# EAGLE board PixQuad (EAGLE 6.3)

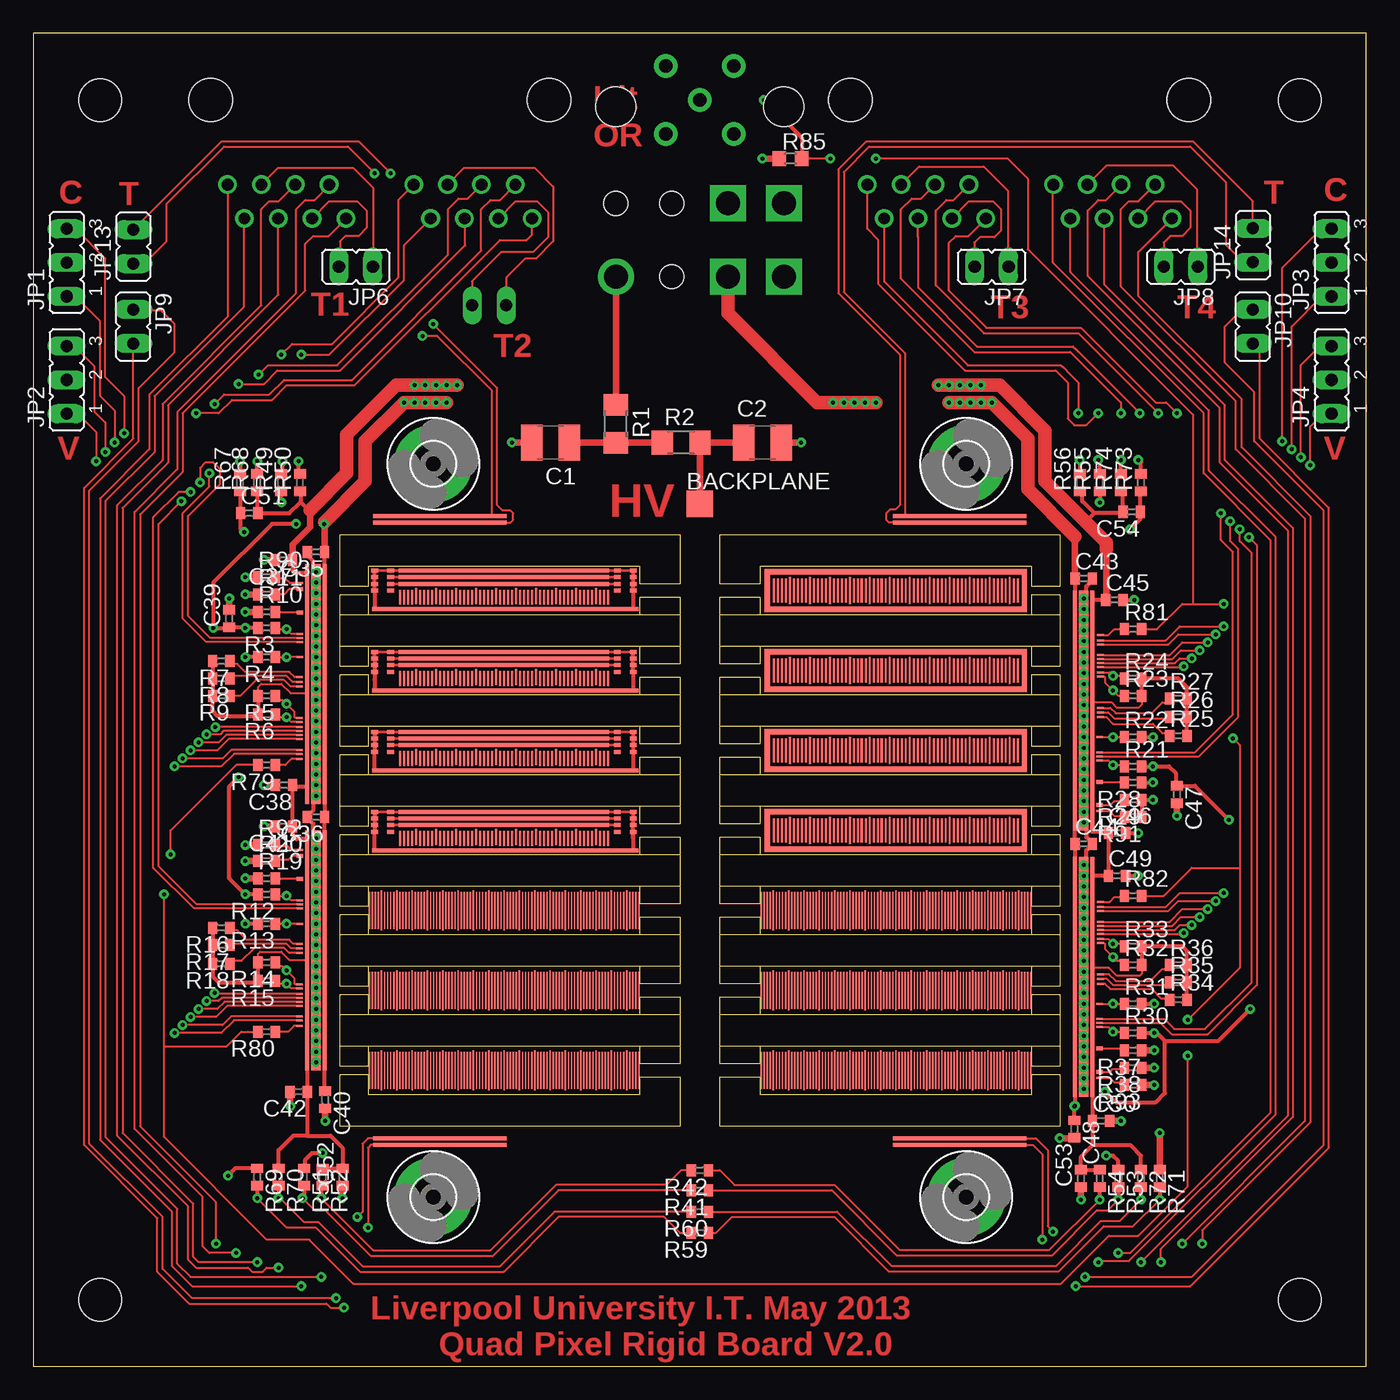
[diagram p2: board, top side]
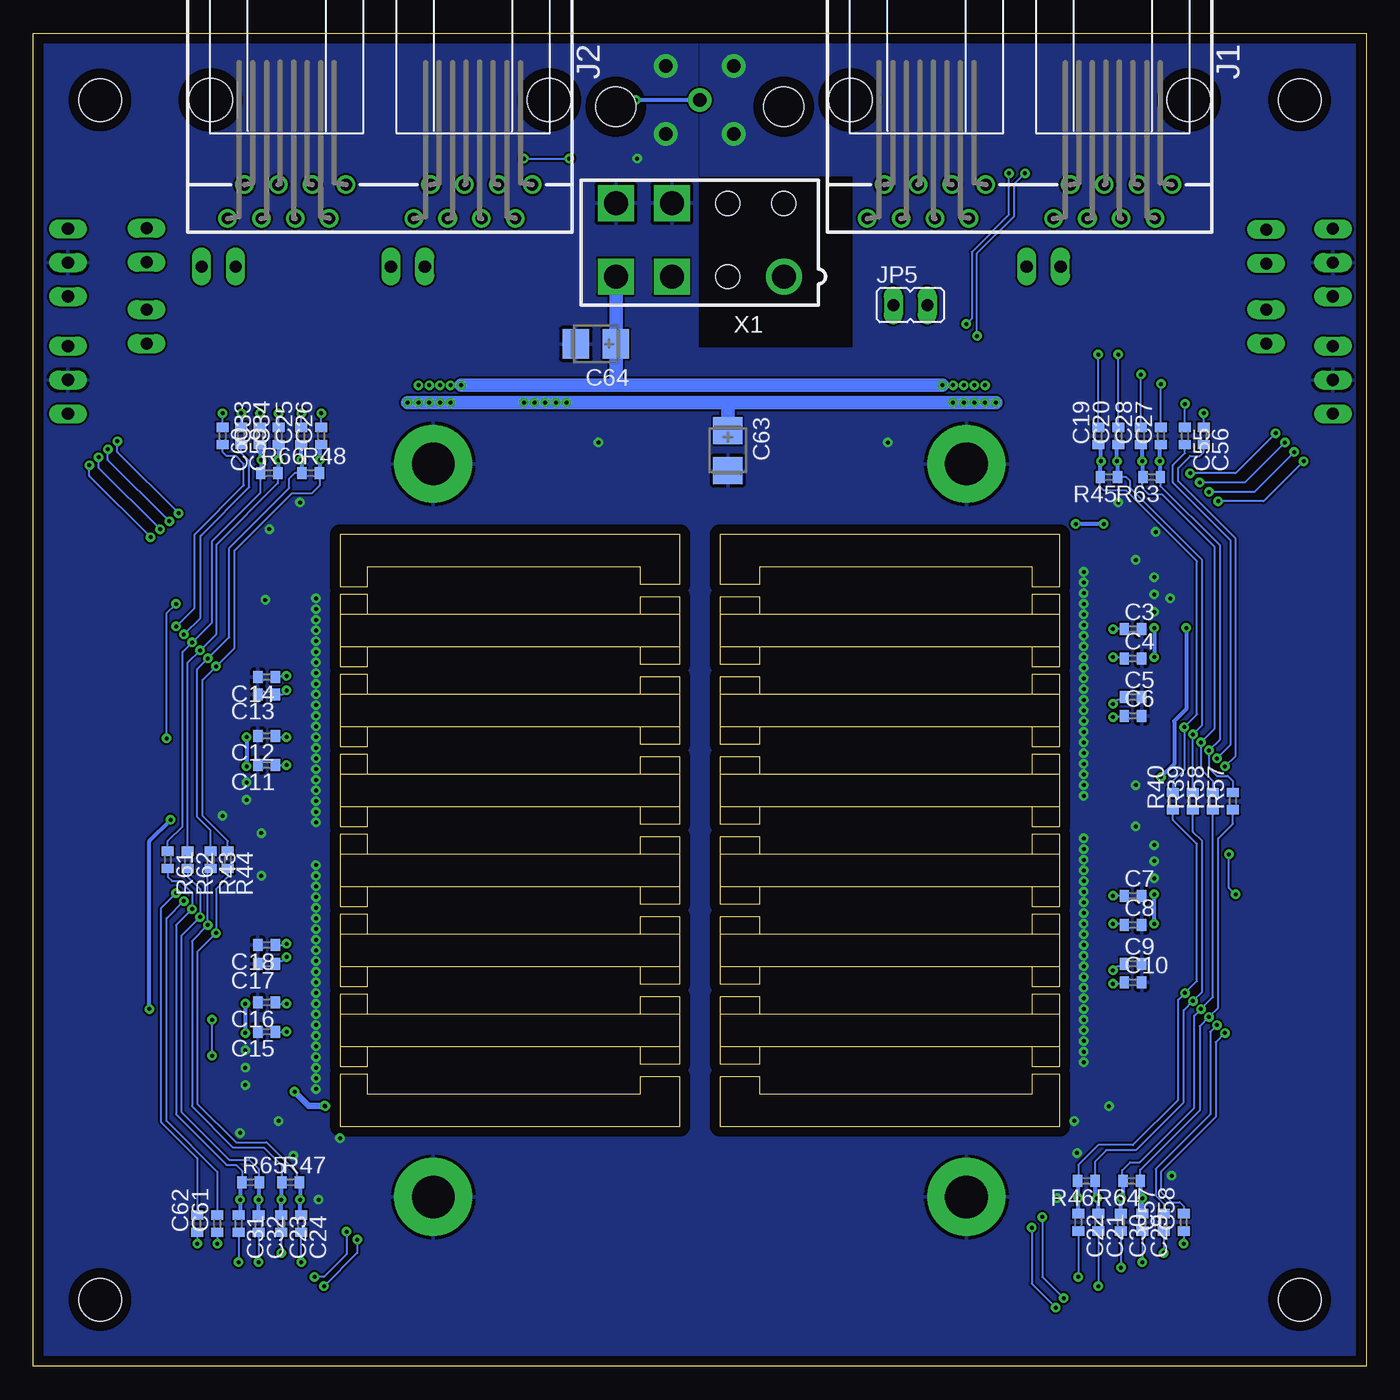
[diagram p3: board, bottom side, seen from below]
Size 100 x 100 mm. Coordinates in mm from the lower left corner, seen from the top.
Outline: 0,0 100,0 100,100 0,100 0,0
Copper layers (1+2*15+16): Top 0.035mm / dielectric 1.5mm / Route2 0.035mm / dielectric 0.15mm / Route15 0.035mm / dielectric 0.2mm / Bottom 0.035mm
Design rules "default *": minimum track width 10mil, minimum drill 24mil, track to track 6mil, track to pad 6mil, pad to pad 6mil, via to via 6mil, smd to smd 6mil, copper to edge 30mil, drill to drill 8mil, minimum pad ring 10mil, minimum via ring 8mil, stop-mask expansion 4mil, vias tented up to drill 0mil, thermal gap 10mil
Holes 3.2 mm at 5,5 5,95 95,95 95,5

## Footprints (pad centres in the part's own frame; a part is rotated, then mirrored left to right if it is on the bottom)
TP20SQ = smd 2 x 2: TP 0,0
C1210 = smd 1.6 x 2.7: 1 -1.4,0; 2 1.4,0
C0402 = smd 0.7 x 0.9: 1 -0.65,0; 2 0.65,0
CT3528 = smd 2 x 2.2: + -1.5,0; - 1.5,0
3,2-PAD = drill 3.2 pad 5.842: B3,2 0,0
557560-1 = drill 0.889: 1-1 -11.43,6.35; 1-2 -10.16,8.89; 1-3 -8.89,6.35; 1-4 -7.62,8.89; 1-5 -6.35,6.35; 1-6 -5.08,8.89; 1-7 -3.81,6.35; 1-8 -2.54,8.89; 2-1 2.54,6.35; 2-2 3.81,8.89; 2-3 5.08,6.35; 2-4 6.35,8.89; 2-5 7.62,6.35; 2-6 8.89,8.89; 2-7 10.16,6.35; 2-8 11.43,8.89 | hole 3.251: -12.7,0; 12.7,0
JP2 = drill 0.914 long: 1 -2.54,0; 2 0,0; 3 2.54,0
JP1 = drill 0.914 long: 1 0,-1.27; 2 0,1.27
JUMPER_JP1 = drill 0.914 long: 1 0,-1.27; 2 0,1.27
R1206 = smd 1.6 x 1.803: 1 -1.422,0; 2 1.422,0
R0402 = smd 0.7 x 0.9: 1 -0.65,0; 2 0.65,0
RCL_R0603 = smd 1 x 1.1: 1 -0.85,0; 2 0.85,0
FE-I4 = smd 0.15 x 0.5: AINJ(46) -4.45,-2; CAPM(47) -4.15,-2; CLK+(93) 2.55,-2.05; CLK-(92) 2.25,-2.05; CMD+(95) 3.15,-2.05; CMD-(94) 2.85,-2.05; DOB+(103) 3.95,-2.05; DOB-(104) 4.25,-2.05; GA0(67) -1.5,-2.05; GA1(68) -1.15,-2.05; GA2(69) -0.8,-2.05; P$1 4.65,-2.05; RESET1(45) -4.75,-2; RESET2(56) -3,-2; RESET3(88) 1.55,-2.05; RESET4(89) 1.85,-2.05; TDAC(11) -8.55,-2 | smd 18 x 0.7: GND -1,-0.8 | smd 0.3 x 0.5: IREF(33,34) -6.35,-2; VTHR(24,16) -8.1,-2 | smd 18 x 0.3: VDDA -1,-0.15; VDDD -1,-1.45
PA2 = smd 0.1 x 2.8: P$1 0,0; P$2 0.23,0; P$3 0.46,0; P$4 0.69,0; P$6 1.15,0; P$7 1.38,0; P$8 1.61,0; P$9 1.84,0; P$11 2.3,0; P$12 2.53,0; P$13 2.76,0; P$14 2.99,0; P$16 3.45,0; P$17 3.68,0; P$18 3.91,0; P$19 4.14,0; P$21 4.6,0; P$22 4.83,0; P$23 5.06,0; P$24 5.29,0; P$26 5.75,0; P$27 5.98,0; P$28 6.21,0; P$29 6.44,0; P$31 6.9,0; P$32 7.13,0; P$33 7.36,0; P$34 7.59,0; P$36 8.05,0; P$37 8.28,0; P$38 8.51,0; P$39 8.74,0; P$41 9.2,0; P$42 9.43,0; P$43 9.66,0; P$44 9.89,0; P$46 10.35,0; P$47 10.58,0; P$48 10.81,0; P$49 11.04,0; P$51 11.5,0; P$52 11.73,0; P$53 11.96,0; P$54 12.19,0; P$56 12.65,0; P$57 12.88,0; P$58 13.11,0; P$59 13.34,0; P$61 13.8,0; P$62 14.03,0; P$63 14.26,0; P$64 14.49,0; P$66 14.95,0; P$67 15.18,0; P$68 15.41,0; P$69 15.64,0; P$71 16.1,0; P$72 16.33,0; P$73 16.56,0; P$74 16.79,0; P$76 17.25,0; P$77 17.48,0; P$78 17.71,0; P$79 17.94,0; P$81 18.4,0; P$82 18.63,0; P$83 18.86,0; P$84 19.09,0; P$86 19.55,0; P$87 19.78,0; P$88 20.01,0; P$89 20.24,0 | smd 0.1 x 3: P$5 0.92,0; P$10 2.07,0; P$15 3.22,0; P$20 4.37,0; P$25 5.52,0; P$30 6.67,0; P$35 7.82,0; P$40 8.97,0; P$45 10.12,0; P$50 11.27,0; P$55 12.42,0; P$60 13.57,0; P$65 14.72,0; P$70 15.87,0; P$75 17.02,0; P$80 18.17,0; P$85 19.32,0
PA3 = smd 15.8 x 0.3: P$1 10.2,0.7; P$2 10.2,0.2; P$3 10.2,-0.3 | smd 0.5 x 0.3: P$4 0.5,0.7; P$5 0.5,0.2; P$6 0.5,-0.3; P$7 0.5,-0.8; P$8 1.7,0.7; P$9 1.7,0.2; P$10 1.7,-0.3; P$11 1.7,-0.8; P$12 18.7,0.7; P$13 18.7,0.2; P$14 18.7,-0.3; P$15 18.7,-0.8; P$16 19.9,0.7; P$17 19.9,0.2; P$18 19.9,-0.3; P$19 19.9,-0.8 | smd 20 x 0.3: P$20 10.3,-2.2 | smd 0.15 x 1.1: P$21 2.4,-1.3; P$22 2.7,-1.3; P$23 3,-1.3; P$24 3.3,-1.3; P$26 3.9,-1.3; P$27 4.2,-1.3; P$28 4.5,-1.3; P$29 4.8,-1.3; P$31 5.4,-1.3; P$32 5.7,-1.3; P$33 6,-1.3; P$34 6.3,-1.3; P$36 6.9,-1.3; P$37 7.2,-1.3; P$38 7.5,-1.3; P$39 7.8,-1.3; P$41 8.4,-1.3; P$42 8.7,-1.3; P$43 9,-1.3; P$44 9.3,-1.3; P$46 9.9,-1.3; P$47 10.2,-1.3; P$48 10.5,-1.3; P$49 10.8,-1.3; P$51 11.4,-1.3; P$52 11.7,-1.3; P$53 12,-1.3; P$54 12.3,-1.3; P$56 12.9,-1.3; P$57 13.2,-1.3; P$58 13.5,-1.3; P$59 13.8,-1.3; P$61 14.4,-1.3; P$62 14.7,-1.3; P$63 15,-1.3; P$64 15.3,-1.3; P$66 15.9,-1.3; P$67 16.2,-1.3; P$68 16.5,-1.3; P$69 16.8,-1.3; P$71 17.4,-1.3; P$72 17.7,-1.3; P$73 18,-1.3 | smd 0.15 x 1.2: P$25 3.6,-1.2; P$30 5.1,-1.2; P$35 6.6,-1.2; P$40 8.1,-1.2; P$45 9.6,-1.2; P$50 11.1,-1.2; P$55 12.6,-1.2; P$60 14.1,-1.2; P$65 15.6,-1.2; P$70 17.1,-1.2
PA1 = smd 19.7 x 0.4: P$1 9.9,1.4; P$2 9.9,-1.4 | smd 0.15 x 1.8: P$3 0.75,0; P$4 1.05,0; P$5 1.35,0; P$6 1.65,0; P$8 2.25,0; P$9 2.55,0; P$10 2.85,0; P$11 3.15,0; P$13 3.75,0; P$14 4.05,0; P$15 4.35,0; P$16 4.65,0; P$18 5.25,0; P$19 5.55,0; P$20 5.85,0; P$21 6.15,0; P$23 6.75,0; P$24 7.05,0; P$25 7.35,0; P$26 7.65,0; P$28 8.25,0; P$29 8.55,0; P$30 8.85,0; P$31 9.15,0; P$33 9.75,0; P$34 10.05,0; P$35 10.35,0; P$36 10.65,0; P$38 11.25,0; P$39 11.55,0; P$40 11.85,0; P$41 12.15,0; P$43 12.75,0; P$44 13.05,0; P$45 13.35,0; P$46 13.65,0; P$48 14.25,0; P$49 14.55,0; P$50 14.85,0; P$51 15.15,0; P$53 15.75,0; P$54 16.05,0; P$55 16.35,0; P$56 16.65,0; P$58 17.25,0; P$59 17.55,0; P$60 17.85,0; P$61 18.15,0; P$63 18.75,0; P$64 19.05,0 | smd 0.15 x 2: P$7 1.95,0; P$12 3.45,0; P$17 4.95,0; P$22 6.45,0; P$27 7.95,0; P$32 9.45,0; P$37 10.95,0; P$42 12.45,0; P$47 13.95,0; P$52 15.45,0; P$57 16.95,0; P$62 18.45,0 | smd 0.4 x 2.4: P$65 19.55,0; P$66 0.25,0
DORT = smd 10 x 0.3: P$1 5,0; P$2 5,0.5
FE-I4_5566-8 = drill 1.8: 1 6.3,-2.75 | drill 1.8 square: 3 -2.1,-2.75; 4 -6.3,-2.75; 7 -2.1,2.75; 8 -6.3,2.75 | hole 1.8: 2.1,-2.75; 2.1,2.75; 6.3,2.75 | hole 3: -6.3,10; 6.3,10

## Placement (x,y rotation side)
BACKPLANE  TPSQTP20SQ  [TP20SQ]  50,64.7 0 top
C1  10n  [C1210]  38.8,69.3 180 top
C2  10n  [C1210]  54.7,69.3 0 top
C3  100n  [C0402]  17.5,55.3 0 bottom
C4  100n  [C0402]  17.5,53.1 0 bottom
C5  100n  [C0402]  17.5,50.2 0 bottom
C6  100n  [C0402]  17.5,48.8 0 bottom
C7  100n  [C0402]  17.5,35.3 0 bottom
C8  100n  [C0402]  17.5,33.1 0 bottom
C9  100n  [C0402]  17.5,30.2 0 bottom
C10  100n  [C0402]  17.5,28.8 0 bottom
C11  100n  [C0402]  82.5,45.1 180 bottom
C12  100n  [C0402]  82.5,47.3 180 bottom
C13  100n  [C0402]  82.5,50.4 180 bottom
C14  100n  [C0402]  82.5,51.7 180 bottom
C15  100n  [C0402]  82.5,25.1 180 bottom
C16  100n  [C0402]  82.5,27.3 180 bottom
C17  100n  [C0402]  82.5,30.2 180 bottom
C18  100n  [C0402]  82.5,31.6 180 bottom
C19  100n  [C0402]  20.1,69.8 90 bottom
C20  100n  [C0402]  18.6,69.8 90 bottom
C21  100n  [C0402]  20.1,10.8 270 bottom
C22  100n  [C0402]  21.6,10.8 270 bottom
C23  100n  [C0402]  81.4,10.7 270 bottom
C24  100n  [C0402]  79.9,10.7 270 bottom
C25  100n  [C0402]  79.9,69.8 90 bottom
C26  100n  [C0402]  78.4,69.8 90 bottom
C27  100n  [C0402]  15.4,69.8 90 bottom
C28  100n  [C0402]  16.9,69.8 90 bottom
C29  100n  [C0402]  16.8,10.8 270 bottom
C30  100n  [C0402]  18.4,10.8 270 bottom
C31  100n  [C0402]  84.6,10.7 270 bottom
C32  100n  [C0402]  83.1,10.7 270 bottom
C33  100n  [C0402]  83,69.8 90 bottom
C34  100n  [C0402]  81.6,69.8 90 bottom
C35  100n  [C0402]  21.2,61.1 180 top
C36  100n  [C0402]  21.2,41.2 180 top
C37  100n  [C0402]  18.8,60.5 180 top
C38  100n  [C0402]  18.8,43.6 180 top
C39  100n  [C0402]  14.7,56.1 90 top
C40  100n  [C0402]  21.9,20 270 top
C41  100n  [C0402]  18.8,40.5 180 top
C42  100n  [C0402]  19.9,20.6 180 top
C43  100n  [C0402]  78.8,59.1 0 top
C44  100n  [C0402]  78.8,39.2 0 top
C45  100n  [C0402]  81.1,57.5 0 top
C46  100n  [C0402]  81.3,40 0 top
C47  100n  [C0402]  85.8,42.9 270 top
C48  100n  [C0402]  78.1,17.8 270 top
C49  100n  [C0402]  81.3,36.8 0 top
C50  100n  [C0402]  80.1,18.4 0 top
C51  100n  [C0402]  16.2,64 0 top
C52  100n  [C0402]  23.2,14.2 90 top
C53  100n  [C0402]  78.6,14.1 90 top
C54  100n  [C0402]  82.4,64.1 180 top
C55  100n  [C0402]  13.6,69.8 270 bottom
C56  100n  [C0402]  12.2,69.8 270 bottom
C57  100n  [C0402]  15.2,10.8 90 bottom
C58  100n  [C0402]  13.7,10.8 90 bottom
C59  100n  [C0402]  84.4,69.8 270 bottom
C60  100n  [C0402]  85.8,69.8 270 bottom
C61  100n  [C0402]  86.2,10.7 90 bottom
C62  100n  [C0402]  87.7,10.7 90 bottom
C63  10u  [CT3528]  47.9,68.7 270 bottom
C64  10u  [CT3528]  57.8,76.7 180 bottom
H1  [3,2-PAD]  30,67.7 0 top
H2  [3,2-PAD]  30,12.7 0 top
H3  [3,2-PAD]  70,67.7 0 top
H4  substrate contacts  [3,2-PAD]  70,12.7 0 top
J1  [557560-1]  26,95 180 bottom
J2  [557560-1]  74,95 180 bottom
JP1  [JP2]  2.5,82.8 90 top
JP2  [JP2]  2.5,74 90 top
JP3  [JP2]  97.4,82.8 90 top
JP4  [JP2]  97.4,74 90 top
JP5  [JP1]  34.2,79.6 270 bottom
JP6  [JP1]  24.2,82.5 90 top
JP7  [JP1]  71.9,82.5 90 top
JP8  [JP1]  86.1,82.5 90 top
JP9  [JUMPER_JP1]  7.5,78 180 top
JP10  [JUMPER_JP1]  91.5,78 180 top
JP13  [JUMPER_JP1]  7.5,84 0 top
JP14  [JUMPER_JP1]  91.5,84.1 0 top
R1  1k  [R1206]  43.7,70.7 270 top
R2  1k  [R1206]  48.6,69.3 0 top
R3  10k  [R0402]  17.5,55.4 180 top
R4  10k  [R0402]  17.5,53.2 180 top
R5  10k  [R0402]  17.5,50.3 180 top
R6  10k  [R0402]  17.5,48.9 180 top
R7  zero  [R0402]  14.1,52.9 180 top
R8  zero  [R0402]  14.1,51.6 180 top
R9  zero  [R0402]  14.1,50.3 180 top
R10  opt  [R0402]  17.5,56.6 0 top
R11  10k  [R0402]  17.5,57.9 0 top
R12  10k  [R0402]  17.5,35.4 180 top
R13  10k  [R0402]  17.5,33.2 180 top
R14  10k  [R0402]  17.5,30.3 180 top
R15  10k  [R0402]  17.5,28.9 180 top
R16  zero  [R0402]  14.1,32.9 180 top
R17  zero  [R0402]  14.1,31.6 180 top
R18  zero  [R0402]  14.1,30.2 180 top
R19  opt  [R0402]  17.5,36.6 0 top
R20  10k  [R0402]  17.5,37.9 0 top
R21  10k  [R0402]  82.5,45 0 top
R22  10k  [R0402]  82.5,47.2 0 top
R23  10k  [R0402]  82.5,50.3 0 top
R24  10k  [R0402]  82.5,51.6 0 top
R25  zero  [R0402]  85.9,47.3 0 top
R26  zero  [R0402]  85.9,48.7 0 top
R27  zero  [R0402]  85.9,50.1 0 top
R28  opt  [R0402]  82.5,43.8 180 top
R29  10k  [R0402]  82.5,42.5 180 top
R30  10k  [R0402]  82.5,25 0 top
R31  10k  [R0402]  82.5,27.2 0 top
R32  10k  [R0402]  82.5,30.1 0 top
R33  10k  [R0402]  82.5,31.5 0 top
R34  zero  [R0402]  85.9,27.5 0 top
R35  zero  [R0402]  85.9,28.8 0 top
R36  zero  [R0402]  85.9,30.1 0 top
R37  opt  [R0402]  82.5,23.7 180 top
R38  10k  [R0402]  82.5,22.4 180 top
R39  opt  [R0402]  13,42.4 90 bottom
R40  opt  [R0402]  14.5,42.4 90 bottom
R41  opt  [R0402]  50,13.2 180 top
R42  opt  [R0402]  50,14.7 180 top
R43  opt  [R0402]  86.7,38 270 bottom
R44  opt  [R0402]  85.4,38 270 bottom
R45  110  [R0402]  19.3,66.7 180 bottom
R46  110  [R0402]  21,13.9 180 bottom
R47  110  [R0402]  80.7,13.8 0 bottom
R48  110  [R0402]  79.2,67 0 bottom
R49  1k  [R0402]  18.6,66.3 90 top
R50  1k  [R0402]  20,66.3 90 top
R51  1k  [R0402]  20.3,14.2 270 top
R52  1k  [R0402]  21.7,14.2 270 top
R53  1k  [R0402]  81.4,14.1 270 top
R54  1k  [R0402]  80,14.1 270 top
R55  1k  [R0402]  80,66.3 90 top
R56  1k  [R0402]  78.5,66.3 90 top
R57  opt  [R0402]  10,42.4 90 bottom
R58  opt  [R0402]  11.5,42.4 90 bottom
R59  opt  [R0402]  50,10 180 top
R60  opt  [R0402]  50,11.6 180 top
R61  opt  [R0402]  89.9,38 270 bottom
R62  opt  [R0402]  88.4,38 270 bottom
R63  110  [R0402]  16.1,66.7 180 bottom
R64  110  [R0402]  17.6,13.9 180 bottom
R65  110  [R0402]  83.7,13.8 0 bottom
R66  110  [R0402]  82.3,67 0 bottom
R67  1k  [R0402]  15.5,66.3 90 top
R68  1k  [R0402]  16.8,66.3 90 top
R69  1k  [R0402]  16.8,14.2 270 top
R70  1k  [R0402]  18.4,14.2 270 top
R71  1k  [R0402]  84.5,14.1 270 top
R72  1k  [R0402]  83.1,14.1 270 top
R73  1k  [R0402]  83.1,66.3 90 top
R74  1k  [R0402]  81.6,66.3 90 top
R79  1k  [R0402]  17.5,45.1 180 top
R80  1k  [R0402]  17.5,25.1 180 top
R81  1k  [R0402]  82.5,55.3 0 top
R82  1k  [R0402]  82.5,35.3 0 top
R85  51  [RCL_R0603]  56.8,90.6 0 top
R90  200k  [R0402]  17.5,59.2 0 top
R91  200k  [R0402]  82.5,41.2 180 top
R92  200k  [R0402]  17.5,39.1 0 top
R93  200k  [R0402]  82.5,21.1 180 top
U$1  FE_I4ASIC  [FE-I4]  22,50.2 270 top
U$2  FE_I4ASIC  [FE-I4]  22,30.2 270 top
U$3  FE_I4ASIC  [FE-I4]  78,50.2 90 top
U$4  FE_I4ASIC  [FE-I4]  78,30.2 90 top
U$5  PA2  [PA2]  25.2,34.2 0 top
U$6  PA2  [PA2]  25.2,28.2 0 top
U$7  PA2  [PA2]  54.6,34.2 0 top
U$8  PA2  [PA2]  25.2,22.2 0 top
U$9  PA2  [PA2]  54.6,28.2 0 top
U$10  PA2  [PA2]  54.6,22.2 0 top
U$11  PA3  [PA3]  25.1,59 0 top
U$12  PA1  [PA1]  54.8,58.2 0 top
U$13  PA1  [PA1]  54.8,52.2 0 top
U$14  PA1  [PA1]  54.8,46.2 0 top
U$15  PA1  [PA1]  54.8,40.2 0 top
U$16  PA3  [PA3]  25.1,52.9 0 top
U$17  DORT  [DORT]  25.5,63.3 0 top
U$18  DORT  [DORT]  64.5,63.3 0 top
U$19  PA3  [PA3]  25.1,46.9 0 top
U$20  PA3  [PA3]  25.1,40.9 0 top
U$21  DORT  [DORT]  25.5,16.6 0 top
U$22  DORT  [DORT]  64.5,16.6 0 top
X1  FE-I4_5566-8  [FE-I4_5566-8]  50,84.5 0 bottom

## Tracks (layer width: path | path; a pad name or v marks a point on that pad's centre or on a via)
AINJ1  (via drill 0.3)
  Top 0.15: U$1.AINJ(46) 13.25,54.65 11.6,56.3 11.6,63.8 14,66.2 14,67.3 13.5,67.8 12.9,67.8 12.5,67.4 v12.5,66.3 | JP1.1 2.56,80.2 3.2,80.2 5,78.4 5,72.8 6.1,71.7 v6.1,69.3
  Bottom 0.15: v6.1,69.3 9.1,66.3 v12.5,66.3
AINJ2  (via drill 0.3)
  Top 0.15: U$2.AINJ(46) 12.25,34.65 9.4,37.5 9.4,63.2 v11.1,64.9 | JP2.1 3.34,71.46 4.7,70.1 v4.7,67.9
  Bottom 0.15: v4.7,67.9 7.7,64.9 v11.1,64.9
AINJ3  (via drill 0.3)
  Top 0.15: U$3.AINJ(46) 87.45,45.75 90.4,48.7 90.4,61.3 89.8,61.9 v89.8,63.4 | v94.4,68.8 94.4,78 96.6,80.2 97.34,80.2 JP3.1
  Bottom 0.15: v89.8,63.4 94.4,68 v94.4,68.8
AINJ4  (via drill 0.3)
  Top 0.15: U$4.AINJ(46) 84.55,25.75 85.4,24.9 88.1,24.9 91.8,28.6 91.8,61.6 v91.2,62.2 | JP4.1 97.24,71.3 96.6,71.3 95.8,70.5 v95.8,67.6
  Bottom 0.15: v91.2,62.2 95.8,66.8 v95.8,67.6
C1.1  (via drill 0.3)
  Top 0.15: v18.6,75.9 19.4,76.7 22.4,76.7 27.4,81.7 27.4,87.51 J1.2-1 28.5,88.61
  Bottom 0.15: C20.2 v18.6,75.9
C1.2  (via drill 0.3)
  Top 0.15: v20.1,75.9 22.2,75.9 27.8,81.5 27.8,84.1 J1.2-2
  Bottom 0.15: C19.2 v20.1,75.9
C1.4  (via drill 0.3)
  Top 0.15: v15.4,73.7 17.3,73.7 18.3,74.7 23,74.7 32.4,84.1 32.4,86.06 J1.2-4
  Bottom 0.15: C27.2 v15.4,73.7
C1.5  (via drill 0.3)
  Top 0.15: v16.9,74.4 17.6,75.1 22.8,75.1 31.1,83.4 31.1,86.8 31.9,87.6 32.57,87.6 J1.2-5
  Bottom 0.15: C28.2 v16.9,74.4
C1.7  (via drill 0.3)
  Top 0.15: v13.6,72.2 14.3,72.9 17.7,72.9 18.8,74 23.9,74 33.6,83.7 33.6,86.8 34.3,87.5 35.01,87.5 J1.2-7
  Bottom 0.15: C55.1 v13.6,72.2
C1.8  (via drill 0.3)
  Top 0.15: v12.2,71.5 13.9,71.5 14.9,72.5 17.9,72.5 19,73.6 24.1,73.6 35,84.5 37,84.5 37.4,84.9 37.4,86.08 J1.2-8
  Bottom 0.15: C56.1 v12.2,71.5
C2.1  (via drill 0.3)
  Top 0.15: J1.1-1 14.6,88.62 14.6,78.8 8.7,72.9 8.7,68.8 5,65.1 5,17 10.4,11.6 10.4,7.5 11.9,6 v20.1,6
  Bottom 0.15: C21.2 v20.1,6
C2.2  (via drill 0.3)
  Top 0.15: J1.1-2 15.8,86.07 15.8,79.5 9.1,72.8 9.1,68.6 5.4,64.9 5.4,17.2 10.8,11.8 10.8,7.7 11.8,6.7 v21.6,6.7
  Bottom 0.15: C22.2 v21.6,6.7
C2.4  (via drill 0.3)
  Top 0.15: v16.8,7.8 12.4,7.8 12,8.2 12,12.2 6.7,17.5 6.7,64.4 10.1,67.8 10.1,72.1 18.38,80.38 J1.1-4
  Bottom 0.15: C29.2 v16.8,7.8
C2.5  (via drill 0.3)
  Top 0.15: v18.4,7.4 17.5,7.4 17.2,7.1 16.4,7.1 16.1,7.4 12.2,7.4 11.6,8 11.6,12 6.3,17.3 6.3,64.6 9.7,68 9.7,72.2 17.1,79.6 17.1,86.8 17.7,87.4 18.4,87.4 J1.1-5
  Bottom 0.15: C30.2 v18.4,7.4
C2.7  (via drill 0.3)
  Top 0.15: v15.2,8.5 13.2,8.5 12.7,9 12.7,12.7 7.6,17.8 7.6,64.1 10.8,67.3 10.8,71.6 19.7,80.5 19.7,86.8 20.4,87.5 21.1,87.5 22.19,88.59 J1.1-7
  Bottom 0.15: C57.1 v15.2,8.5
C2.8  (via drill 0.3)
  Top 0.15: J1.1-8 22.15,84.8 21,84.8 20.4,84.2 20.4,80.7 11.2,71.5 11.2,67.1 8,63.9 8,18 13.7,12.3 v13.7,9.2
  Bottom 0.15: C58.1 v13.7,9.2
C3.1  (via drill 0.3)
  Top 0.15: v79.9,71.5 79,70.6 78.1,70.6 77.6,71.1 77.6,73.8 76.7,74.7 69.9,74.7 63.4,81.2 63.4,84.5 62.57,85.33 J2.1-1
  Bottom 0.15: C25.2 v79.9,71.5
C3.2  (via drill 0.3)
  Top 0.15: J2.1-2 63.84,81.36 70.1,75.1 77.1,75.1 77.3,74.9 77.75,74.45 78.4,73.8 v78.4,71.5
  Bottom 0.15: C26.2 v78.4,71.5
C3.4  (via drill 0.3)
  Top 0.15: J2.1-4 66.38,84.72 66.4,84.7 66.4,80.9 70.8,76.5 78,76.5 78.2,76.3 78.35,76.15 v83,71.5
  Bottom 0.15: C33.2 v83,71.5
C3.5  (via drill 0.3)
  Top 0.15: v81.6,71.5 81.6,72.3 77.8,76.1 70.6,76.1 65.1,81.6 65.1,86.8 65.9,87.6 66.6,87.6 J2.1-5
  Bottom 0.15: C34.2 v81.6,71.5
C3.7  (via drill 0.3)
  Top 0.15: v84.4,71.5 78.4,77.5 71.3,77.5 67.7,81.1 67.7,86.7 68.5,87.5 69.04,87.5 J2.1-7
  Bottom 0.15: C59.1 v84.4,71.5
C3.8  (via drill 0.3)
  Top 0.15: v85.8,71.5 85,72.3 84.2,72.3 78.6,77.9 71.5,77.9 68.7,80.7 68.7,84.3 69.2,84.8 70.15,84.8 J2.1-8 71.5,86.07
  Bottom 0.15: C60.1 v85.8,71.5
C4.1  (via drill 0.3)
  Top 0.15: v81.4,8.5 82.3,8.5 92.8,19 92.8,62 87.8,67 87.8,71.5 76.5,82.8 76.5,88.61 J2.2-1
  Bottom 0.15: C23.2 v81.4,8.5
C4.2  (via drill 0.3)
  Top 0.15: v79.9,7.8 80,7.9 82.2,7.9 93.2,18.9 93.2,62.2 88.2,67.2 88.2,71.7 77.81,82.09 J2.2-2
  Bottom 0.15: v79.9,7.8 C24.2
C4.4  (via drill 0.3)
  Top 0.15: v84.6,7.8 84.6,8.8 94.5,18.7 94.5,62.9 89.4,68 89.4,72.1 80.35,81.15 J2.2-4
  Bottom 0.15: C31.2 v84.6,7.8
C4.5  (via drill 0.3)
  Top 0.15: v83.1,7.8 94.1,18.8 94.1,62.7 89,67.8 89,71.9 79.1,81.8 79.1,86.7 79.9,87.5 80.47,87.5 J2.2-5
  Bottom 0.15: C32.2 v83.1,7.8
C4.7  (via drill 0.3)
  Top 0.15: v86.2,9.2 95.4,18.4 95.4,63.6 90.2,68.8 90.2,72.4 81.6,81 81.6,86.8 82.2,87.4 82.91,87.4 J2.2-7
  Bottom 0.15: C61.1 v86.2,9.2
C4.8  (via drill 0.3)
  Top 0.15: J2.2-8 85.41,86.11 82.9,83.6 82.9,80.3 90.65,72.55 90.65,68.95 95.8,63.8 95.8,18.3 87.7,10.2 v87.7,9.2
  Bottom 0.15: C62.1 v87.7,9.2
CAPM1  (via drill 0.3)
  Top 0.15: U$1.CAPM(47) 12.95,54.35 11.2,56.1 11.2,64 13.2,66 v13.2,67 | JP1.3 2.54,85.3 3.2,85.3 5.4,83.1 5.4,74.2 6.8,72.8 v6.8,70
  Bottom 0.15: v6.8,70 9.8,67 v13.2,67
CAPM2  (via drill 0.3)
  Top 0.15: U$2.CAPM(47) 12.05,34.35 9,37.4 9,63.7 10.9,65.6 v11.8,65.6 | 2.54,76.5 JP2.3 3.06,76.54 4.6,75 4.6,71.6 5.4,70.8 v5.4,68.6
  Bottom 0.15: v5.4,68.6 8.4,65.6 v11.8,65.6
CAPM3  (via drill 0.3)
  Top 0.15: U$3.CAPM(47) 87.15,46.05 90,48.9 90,61.1 89.1,62 v89.1,64 | v93.7,69.4 93.7,82.4 96.7,85.4 97.34,85.4 JP3.3
  Bottom 0.15: v89.1,64 93.7,68.6 v93.7,69.4
CAPM4  (via drill 0.3)
  Top 0.15: U$4.CAPM(47) 84.85,26.05 85.6,25.3 87.9,25.3 91.4,28.8 91.4,61 90.5,61.9 v90.5,62.8 | v95.1,68.2 95.1,75.1 96.6,76.6 97.34,76.6 JP4.3
  Bottom 0.15: v90.5,62.8 95.1,67.4 v95.1,68.2
CLK1+  (via drill 0.3)
  Top 0.15: U$1.CLK+(93) 14.25,47.65 14,47.4 v13,47.4
  Top 0.3: R49.2 18.7,66.95 v18.7,67.9
  Bottom 0.15: R39.2 v13,47.4 12.3,48.1 12.3,60.5 17.7,65.9 17.7,66.4 18,66.7 R45.1 18.65,66.9 R49.2
  Bottom 0.3: C20.1 18.7,69.05 v18.7,67.9 18.65,67.85 R45.1
CLK1-  (via drill 0.3)
  Top 0.15: U$1.CLK-(92) v13.65,47.95
  Top 0.3: R50.2 19.9,66.95 v19.9,67.9
  Bottom 0.15: R40.2 14.5,43.9 13.65,44.75 v13.65,47.95 12.7,48.9 12.7,60.4 18,65.7 19.7,65.7 20,66 20,66.65 R45.2
  Bottom 0.3: C19.1 19.9,68.95 v19.9,67.9 19.95,67.85 R45.2
CLK2+  (via drill 0.3)
  Top 0.15: U$2.CLK+(93) 14.15,27.65 13.9,27.4 v13,27.4 | R41.2 39.4,13.2 34.5,8.3 25.3,8.3 21.9,11.7 21.1,11.7 v20.2,12.6
  Top 0.3: 20.2,13.45 R51.2 20.3,12.7 v20.2,12.6
  Bottom 0.15: R39.1 13,40.1 12.3,39.4 12.3,28.1 v13,27.4 13.7,26.7 13.7,19.8 17.3,16.2 19.5,16.2 20.35,15.35 R46.1
  Bottom 0.3: R46.1 20.35,12.75 v20.2,12.6 20.1,12.5 C21.1
CLK2-  (via drill 0.3)
  Top 0.15: U$2.CLK-(92) 13.65,27.95 v13.6,28 | R42.2 48.6,14.7 47.5,13.6 39.2,13.6 34.3,8.7 25.5,8.7 v21.6,12.6
  Top 0.3: R52.2 21.6,13.45 v21.6,12.6
  Bottom 0.15: v13.6,28 12.7,28.9 12.7,39.2 14.5,41 R40.1 | v13.6,28 13.7,27.9 | v13.6,28 14.1,27.5 14.1,20 17.5,16.6 20.1,16.6 21.6,15.1 21.6,13.95 R46.2 | 21.65,12.65 v21.6,12.6
  Bottom 0.3: R46.2 21.65,12.65 | C22.1 v21.6,12.6
CLK3+  (via drill 0.3)
  Top 0.15: U$3.CLK+(93) 85.65,52.75 86,53.1 v86.9,53.1
  Top 0.3: R55.2 80,67.9 v79.9,68
  Bottom 0.15: R43.1 86.7,40.2 87.7,41.2 87.7,52.3 v86.9,53.1 85.3,54.7 85.3,61.4 80.8,65.9 80.8,66.6 80.4,67 R48.1
  Bottom 0.3: C25.1 v79.9,68 79.85,67.95 R48.1
CLK3-  (via drill 0.3)
  Top 0.15: U$3.CLK-(92) 86.25,52.45 v86.3,52.5
  Top 0.3: v78.5,68 R56.2
  Bottom 0.15: R44.1 85.4,39.4 87.3,41.3 87.3,51.5 v86.3,52.5 84.9,53.9 84.9,61.2 80.6,65.5 79.1,65.5 78.5,66.1 R56.2 R48.2
  Bottom 0.3: C26.1 78.5,69.05 v78.5,68 78.5,67.05 R48.2
CLK4+  (via drill 0.3)
  Top 0.15: U$4.CLK+(93) 85.65,32.75 86,33.1 v86.9,33.1 | R41.1 59.9,13.2 64.8,8.3 76.4,8.3 79.8,11.7 80.6,11.7 v81.4,12.5
  Top 0.3: R53.2 v81.4,12.5
  Bottom 0.15: R43.2 86.9,37.15 v86.9,33.1 88.1,31.9 88.1,19.5 85,16.4 82.7,16.4 81.35,15.05 R47.1
  Bottom 0.3: C23.1 v81.4,12.5 81.4,13.75 R47.1
CLK4-  (via drill 0.3)
  Top 0.15: U$4.CLK-(92) 86.25,32.45 v86.3,32.5 | R42.1 51.5,14.7 52.6,13.6 60.1,13.6 65,8.7 76.2,8.7 v80,12.5
  Top 0.3: v80,12.5 R54.2
  Bottom 0.15: R44.2 85.4,36.7 86.3,35.8 v86.3,32.5 87.7,31.1 87.7,19.7 84.8,16.8 82.5,16.8 80.2,14.5 80.2,13.95 R47.2
  Bottom 0.3: C24.1 80,11.45 v80,12.5 80,13.75 R47.2
CMD1+  (via drill 0.3)
  Top 0.15: U$1.CMD+(95) 14.65,47.05 13.8,46.2 v11.8,46.2
  Top 0.3: v15.5,67.9 R67.2
  Bottom 0.15: R57.2 10,43.9 10.4,44.3 11.2,44.3 11.8,44.9 v11.8,46.2 11,47 11,61.6 15.45,66.05 R63.1
  Bottom 0.3: C27.1 15.5,69.05 v15.5,67.9 15.45,67.85 R63.1
CMD1-  (via drill 0.3)
  Top 0.15: U$1.CMD-(94) 14.45,47.35 13.9,46.8 v12.4,46.8
  Top 0.3: R68.2 v16.8,67.9
  Bottom 0.15: R58.2 11.5,43.9 12.4,44.8 v12.4,46.8 11.4,47.8 11.4,61.5 15.3,65.4 16.3,65.4 16.8,65.9 16.8,66.65 R63.2
  Bottom 0.3: C28.1 16.8,69.05 v16.8,67.9 16.75,67.85 R63.2
CMD2+  (via drill 0.3, 0.3 pad 0.7)
  Top 0.15: U$2.CMD+(95) 14.55,27.05 13.7,26.2 v11.8,26.2 | R59.2 48.5,10 47.3,11.2 39.4,11.2 35.3,7.1 24.5,7.1 21.2,10.4 19,10.4 v16.8,12.6
  Top 0.3: 17.1,13.45 R69.2 v16.8,12.6
  Bottom 0.15: R57.1 10,40.7 11.1,39.6 11.1,26.9 v11.8,26.2 12.5,25.5 12.5,19.2 16.95,14.75 R64.1
  Bottom 0.3: C29.1 v16.8,12.6 16.95,12.75 R64.1
CMD2-  (via drill 0.3)
  Top 0.15: U$2.CMD-(94) 14.35,27.35 13.8,26.8 v12.4,26.8 | R60.2 39.1,11.6 35,7.5 24.7,7.5 21.4,10.8 20.3,10.8 18.5,12.6 v18.4,12.6
  Top 0.3: 18.6,13.35 R70.2 v18.4,12.6
  Bottom 0.15: v12.4,26.8 11.5,27.7 R58.1 | v12.4,26.8 12.5,26.7 | v12.4,26.8 12.9,26.3 12.9,19.4 17,15.3 17.7,15.3 18.3,14.7 18.3,13.95 R64.2
  Bottom 0.3: R64.2 18.25,12.75 v18.4,12.6 C30.1
CMD3+  (via drill 0.3)
  Top 0.15: U$3.CMD+(95) 85.25,53.35 86.2,54.3 v88.1,54.3
  Top 0.3: R73.2 83.1,67.8 v82.9,68
  Bottom 0.15: R61.1 89.9,39.4 88.8,40.5 88.8,53.6 v88.1,54.3 86.6,55.8 86.6,61.9 83,65.5 83,66.95 R66.1 82.9,66.95
  Bottom 0.3: C33.1 83,68.1 v82.9,68 82.9,67.05 R66.1
CMD3-  (via drill 0.3)
  Top 0.15: U$3.CMD-(94) 85.45,53.05 86.1,53.7 v87.5,53.7
  Top 0.3: R74.2 v81.6,68
  Bottom 0.15: R62.1 88.4,52.8 v87.5,53.7 86.25,54.95 86.25,61.65 81.65,66.25 R66.2
  Bottom 0.3: C34.1 v81.6,68 81.6,67.05 R66.2
CMD4+  (via drill 0.3)
  Top 0.15: U$4.CMD+(95) 85.25,33.35 86.2,34.3 v88.1,34.3 | R59.1 51.2,10 52.4,11.2 60.1,11.2 64.2,7.1 76.9,7.1 80.3,10.5 82.5,10.5 v84.5,12.5
  Top 0.3: R71.2 v84.5,12.5
  Bottom 0.15: R61.2 89.9,36.7 89.6,36.4 89,36.4 88.1,35.5 v88.1,34.3 89.3,33.1 89.3,18.9 85.5,15.1 84.8,15.1 84.35,14.65 R65.1
  Bottom 0.3: R65.1 84.5,13.65 v84.5,12.5 84.5,11.45 C31.1
CMD4-  (via drill 0.3)
  Top 0.15: U$4.CMD-(94) 85.45,33.05 86.1,33.7 v87.5,33.7 | R60.1 60.3,11.6 64.4,7.5 76.7,7.5 80.1,10.9 81.5,10.9 v83.1,12.5
  Top 0.3: v83.1,12.5 R72.2
  Bottom 0.15: R62.2 88.4,36.7 87.5,35.8 v87.5,33.7 88.9,32.3 88.9,19.1 85.3,15.5 83.8,15.5 83.1,14.8 83.1,13.85 R65.2
  Bottom 0.3: R65.2 83.1,13.75 v83.1,12.5 C32.1
DOB1+  (via drill 0.3)
  Top 0.15: U$1.DOB+(103) 14.85,46.25 14.2,45.6 v11.2,45.6
  Bottom 0.15: v11.2,45.6 10.2,46.6 10.2,62 14.5,66.3 14.5,67.6 13.6,68.5 C55.2
DOB1-  (via drill 0.3)
  Top 0.15: U$1.DOB-(104) 15.05,45.95 14.1,45 v10.6,45
  Bottom 0.15: v10.6,45 9.8,45.8 9.8,62.1 14.1,66.4 14.1,67.4 13.2,68.3 12.5,68.3 12.2,68.6 C56.2
DOB2+  (via drill 0.3)
  Top 0.15: U$2.DOB+(103) 14.85,26.25 14.2,25.6 v11.2,25.6
  Bottom 0.15: v11.2,25.6 11.7,25.1 11.7,18.9 15.8,14.8 15.8,12.8 15.2,12.2 C57.2
DOB2-  (via drill 0.3)
  Top 0.15: U$2.DOB-(104) 15.05,25.95 14.1,25 v10.6,25
  Bottom 0.15: v10.6,25 11.3,24.3 11.3,18.7 15.4,14.6 15.4,13.1 14.6,12.3 14,12.3 13.7,12 C58.2
DOB3+  (via drill 0.3)
  Top 0.15: U$3.DOB+(103) 85.15,54.15 85.9,54.9 v88.7,54.9
  Bottom 0.15: v88.7,54.9 87.45,56.15 87.45,62.3 83.8,65.95 83.8,67.9 84.4,68.5 C59.2
DOB3-  (via drill 0.3)
  Top 0.15: U$3.DOB-(104) 84.95,54.45 86,55.5 v89.3,55.5
  Bottom 0.15: v89.3,55.5 87.9,56.9 87.9,62.4 84.2,66.1 84.2,67.7 84.8,68.3 85.5,68.3 85.8,68.6 C60.2
DOB4+  (via drill 0.3)
  Top 0.15: U$4.DOB+(103) 85.15,34.15 85.9,34.9 v88.7,34.9
  Bottom 0.15: v88.7,34.9 90,33.6 90,18.4 86.2,14.6 C61.2
DOB4-  (via drill 0.3)
  Top 0.15: U$4.DOB-(104) 84.95,34.45 86,35.5 v89.3,35.5
  Bottom 0.15: v89.3,35.5 90.4,34.4 90.4,18.3 87.7,15.6 C62.2
GND  (via drill 0.3, 0.3 pad 0.7, 1 pad 1.78)
  Top 0.3: v18.6,64.8 R49.1 | R51.1 20.4,14.95 20.4,15.5 20.9,16 v21.7,16 | R28.1 v84,43.8 | v84,42.5 R29.1 R91.1 | R69.1 15.15,14.85 v14.6,14.3 | R53.1 81.4,15.4 81,15.8 v80.5,15.8 | 19.25,19.55 v19.3,19.5 | 20.55,61.05 C35.2 20.55,60.85 21,60.4 21,59.8 v21.2,59.6 | C36.2 20.55,41.35 | 20.55,41.05 C36.2 | R67.1 15.5,64.05 C51.1 15.55,62.85 v15.8,62.6 | v78.8,57.6 79,57.6 79,58.5 79.45,58.95 C43.2 | v21.2,42.8 21,42.6 21,41.7 20.55,41.25 | v21.2,39.6 21,39.8 21,40.7 20.55,41.15 C36.2 | v78.8,37.6 79,37.8 79,38.7 79.45,39.15 | v78.8,40.8 79,40.6 79,39.7 79.45,39.25 C44.2 | C45.2 v82.6,57.5 | C46.2 v82.9,40 | C49.2 v82.9,36.8 | R55.1 v80,64.8 | R73.1 83.05,65.6 C54.1 83.05,63.55 v82.3,62.8 | v78.8,48.8 U$3.GND | U$4.GND v78.8,28.8 | U$2.GND v21.2,30.8
  Top 0.5: R10.1 v15.9,56.6 | R19.1 v15.9,36.6 | R37.1 v84.1,23.7 | C53.1 v78.6,12.5 | R20.1 v15.9,37.9 | R92.1 v15.9,39.1 | R90.1 v15.9,59.2 | R11.1 v15.9,57.9 | R38.1 v84.1,22.4 | R93.1 v84.1,21.1 | C52.1 v23.2,12.6 | C2.2 v57.6,69.3 | C1.2 v35.9,69.3 | C40.2 v21.9,18.4 | C42.2 19.25,19.55 | C41.2 v17.3,40.5 | C38.2 v17.3,43.6 | C39.2 v14.7,57.6 | C50.2 v81.6,18.4 | C37.2 v17.3,60.5 | v21.2,50.8 U$1.GND | R85.1 v54.7,90.6 | C47.2 v85.8,41.3 | C48.2 78.05,17.1 v77,17.1 | R71.1 v84.5,17.5
  other vias: 52.55,97.55 52.55,92.45 47.45,97.55 47.45,92.45 21.2,44.4 21.2,43.6 21.2,45.2 21.2,46 21.2,46.8 21.2,47.6 21.2,48.4 21.2,51.6 21.2,50 21.2,49.2 21.2,58.8 21.2,58 21.2,57.2 21.2,56.4 21.2,55.6 21.2,54.8 21.2,54 21.2,53.2 21.2,52.4 21.2,22.8 21.2,24.4 21.2,23.6 21.2,25.2 21.2,26 21.2,26.8 21.2,27.6 21.2,28.4 21.2,31.6 21.2,30 21.2,29.2 21.2,38.8 21.2,38 21.2,37.2 21.2,36.4 21.2,35.6 21.2,34.8 21.2,34 21.2,33.2 21.2,32.4 78.8,42.4 78.8,41.6 78.8,43.2 78.8,44 78.8,44.8 78.8,45.6 78.8,46.4 78.8,49.6 78.8,48 78.8,47.2 78.8,56.8 78.8,56 78.8,55.2 78.8,54.4 78.8,53.6 78.8,52.8 78.8,52 78.8,51.2 78.8,50.4 78.8,20.8 78.8,22.4 78.8,21.6 78.8,23.2 78.8,24 78.8,24.8 78.8,25.6 78.8,26.4 78.8,29.6 78.8,28 78.8,27.2 78.8,36.8 78.8,36 78.8,35.2 78.8,34.4 78.8,33.6 78.8,32.8 78.8,32 78.8,31.2 78.8,30.4
  pour Bottom: 0.1,99.9 0.1,0.1 99.9,0.1 99.9,99.9 50.1,99.9 50.1,76.4 38.5,76.4 38.5,89.3 50,89.3 50,99.9
HITOR  (via drill 0.3, 1 pad 1.78)
  Top 0.15: R81.2 84.3,55.3 86.2,57.2 87,57.2 | 87,57.2 v89.3,57.2 | R79.2 15.2,45.1 10.3,40.2 v10.3,38.4 | 9.8,24 14.5,24 15.6,25.1 R80.2 16.1,25.1 | 9.8,24 9.8,17.2 17.5,9.5 20.7,9.5 24,6.2 77.1,6.2 80.7,9.8 82.9,9.8 86.6,13.5 v86.6,23.3 | R82.2 84.8,35.3 86.9,37.4 90.5,37.4 | 9.8,24 v9.8,35.4 | v86.6,26 90.5,29.9 90.5,37.4 | 87,57.2 87,71.4 74.6,83.8 74.6,89.1 73.1,90.6 v63.2,90.6 | v59.8,90.6 R85.2 | v90,47.1 90.5,46.6 90.5,37.4
  Top 0.3: v54.8,95 57.65,92.15 R85.2
  Bottom 0.15: v9.8,35.4 10.3,35.9 v10.3,38.4 | v86.6,23.3 v86.6,26 | v90,47.1 90,56.5 v89.3,57.2 | v63.2,90.6 v59.8,90.6
  Bottom 0.3: v50,95 v54.8,95
N$1
  Top 0.5: BACKPLANE.TP 50.02,64.72 R2.2 C2.1
N$2
  Top 0.5: C1.1 43.68,69.3 R1.2 47.16,69.28 R2.1
N$3  (via drill 0.3)
  Top 0.15: v30,78.2 34.8,73.4 34.8,64.6 35.2,64.2 35.8,64.2 36,64 36,63.5 35.8,63.3 U$17.P$1 | JP13.2 14.13,91.9 24.4,91.9 v26.8,89.5
  Bottom 0.15: v26.8,89.5 26.8,86.4 29.6,83.6 29.6,78.6 v30,78.2
N$4  (via drill 0.3)
  Top 0.15: U$1.RESET1(45) 19.35,54.95 v19,55.3 18.25,55.3 R3.1
  Bottom 0.15: C3.1 v19,55.3
N$5  (via drill 0.3)
  Top 0.15: U$1.RESET2(56) v19,53.2 R4.1
  Bottom 0.15: v19,53.2 18.25,53.2 C4.1
N$6  (via drill 0.3)
  Top 0.15: U$1.RESET3(88) 19.65,48.65 19.6,48.7 19.6,49.1 v19,49.7 18.7,50 18.05,50 R5.1
  Bottom 0.15: C5.1 18.25,50 18.7,50 v19,49.7
N$7  (via drill 0.3)
  Top 0.15: U$1.RESET4(89) 19.35,48.35 v19,48.7 18.25,48.7 R6.1
  Bottom 0.15: C6.1 18.15,48.7 v19,48.7
N$8
  Top 0.15: U$1.GA0(67) 19.6,51.7 19.2,52.1 15.9,52.1 15.3,52.7 14.95,52.7 R7.1
N$9
  Top 0.15: U$1.GA1(68) 19.45,51.35 19,51.8 14.95,51.8 R8.1
N$10
  Top 0.15: U$1.GA2(69) 19.3,51 18.8,51.5 16.7,51.5 15.5,50.3 R9.1
N$11
  Top 0.15: U$1.IREF(33,34) 18.2,56.55 R10.2
N$12
  Top 0.15: U$1.VTHR(24,16) 19.2,58.3 18.8,57.9 R11.2
N$13
  Top 0.15: U$1.P$1 19.35,45.55 18.9,45.1 R79.1
N$14
  Top 0.15: U$2.GA0(67) 19.5,31.7 19.2,32 16,32 15.3,32.7 14.95,32.7 R16.1
N$15
  Top 0.15: U$2.GA1(68) 19.35,31.35 19,31.7 14.85,31.7 R17.1
N$16
  Top 0.15: U$2.GA2(69) 19.2,31 18.8,31.4 16.6,31.4 15.6,30.4 14.95,30.4 R18.1
N$17  (via drill 0.3)
  Top 0.15: U$2.RESET1(45) 19.35,34.95 v19,35.3 C7.1 R12.1
  Bottom 0.15: C7.1 v19,35.3
N$18  (via drill 0.3)
  Top 0.15: U$2.RESET2(56) v19,33.2 R13.1
  Bottom 0.15: C8.1 R13.1 v19,33.2
N$19  (via drill 0.3)
  Top 0.15: U$2.RESET3(88) 19.65,28.65 19.6,28.7 19.6,29.1 v19,29.7 18.7,30 18.45,30 R14.1
  Bottom 0.15: C9.1 18.15,30 18.7,30 v19,29.7
N$20  (via drill 0.3)
  Top 0.15: U$2.RESET4(89) 19.35,28.35 v19,28.7 18.35,28.7 R15.1
  Bottom 0.15: C10.1 18.25,28.7 v19,28.7
N$21
  Top 0.15: U$2.P$1 19.55,25.55 19.1,25.1 R80.1
N$22
  Top 0.15: U$3.P$1 80.65,54.85 81.1,55.3 R81.1
N$23
  Top 0.15: U$4.P$1 80.75,34.85 81.1,35.2 81.75,35.2 R82.1
N$24
  Top 0.15: U$1.TDAC(11) 19.25,58.75 18.9,59.1 18.25,59.1 R90.2
N$25
  Top 0.15: U$2.IREF(33,34) 18.2,36.55 R19.2
N$26
  Top 0.15: U$2.VTHR(24,16) 19.4,38.3 19.1,38 18.25,38 R20.2
N$27
  Top 0.15: U$3.TDAC(11) 80.75,41.65 81.1,41.3 81.75,41.3 R91.2
N$28
  Top 0.15: U$2.TDAC(11) 19.35,38.75 19.1,39 18.25,39 R92.2
N$29
  Top 0.15: U$4.TDAC(11) 80.75,21.65 81.1,21.3 81.65,21.3 R93.2
N$30  (via drill 0.3)
  Top 0.15: v29.2,77.3 30.3,77.3 34.4,73.2 34.4,63.9 34.5,63.8 U$17.P$2 | JP13.1 8.33,82.73 10,84.4 10,87.2 14.3,91.5 23.6,91.5 v25.6,89.5
  Bottom 0.15: v29.2,77.3 29.2,83.5 26.4,86.3 26.4,88.7 v25.6,89.5
N$31
  Top 0.15: JP14.1 91.43,82.9 90.7,82.9 89.5,84.1 89.5,88.8 86.8,91.5 62.7,91.5 60.8,89.6 60.8,80.6 65.4,76 65.4,63.8 U$18.P$2
N$32
  Top 0.15: JP14.2 91.5,87.4 87,91.9 62.5,91.9 60.4,89.8 60.4,80.5 65,75.9 65,64.6 64.7,64.3 64.3,64.3 64,64 64,63.5 64.2,63.3 U$18.P$1
N$33
  Top 0.2: U$11.P$4 U$11.P$8 U$11.P$1 U$11.P$12 U$11.P$16
  Top 0.3: U$11.P$16 U$11.P$17 U$11.P$18 U$11.P$19 45,56.8 U$11.P$20 | U$11.P$4 U$11.P$5 U$11.P$6 U$11.P$7 25.6,56.8
N$34
  Top 0.5: X1.1 R1.1
N$35
  Top 0.2: U$16.P$16 U$16.P$12 U$16.P$1 U$16.P$8 U$16.P$4
  Top 0.3: U$16.P$16 U$16.P$17 U$16.P$18 U$16.P$19 45,50.7 U$16.P$20 25.6,50.7 25.6,51.5 U$16.P$7 | U$16.P$6 U$16.P$7 | U$16.P$7 U$16.P$5 U$16.P$4
N$36
  Top 0.2: U$19.P$4 U$19.P$8 U$19.P$1 U$19.P$12 U$19.P$16
  Top 0.3: U$19.P$4 U$19.P$5 U$19.P$6 U$19.P$7 25.6,44.7 U$19.P$20 45,44.7 U$19.P$16 U$19.P$17 U$19.P$18 U$19.P$19
N$37
  Top 0.2: U$20.P$4 U$20.P$8 U$20.P$1 U$20.P$12 U$20.P$16
  Top 0.3: U$20.P$4 U$20.P$5 U$20.P$6 U$20.P$7 25.6,38.7 U$20.P$20 45,38.7 U$20.P$19 | U$20.P$16 U$20.P$17 U$20.P$18 U$20.P$19 | 45,39.6 U$20.P$19
N$38
  Top 0.2: U$11.P$9 U$11.P$2 U$11.P$13
N$39
  Top 0.2: U$16.P$9 U$16.P$2 U$16.P$13
N$40
  Top 0.2: U$19.P$9 U$19.P$2 U$19.P$13
N$41
  Top 0.2: U$20.P$9 U$20.P$2 U$20.P$13
N$42
  Top 0.2: U$20.P$10 U$20.P$3 U$20.P$14
N$43
  Top 0.2: U$19.P$10 U$19.P$3 U$19.P$14
N$44
  Top 0.2: U$16.P$10 U$16.P$3 U$16.P$14
N$45
  Top 0.2: U$11.P$10 U$11.P$3 U$11.P$14
N$46  (via drill 0.3)
  Top 0.15: U$21.P$2 25.1,17.1 24.7,16.7 24.7,11.6 v24.3,11.2 | v22.7,5.1 11.9,5.1 9.7,7.3 9.7,11.2 4.2,16.7 4.2,65.7 7.9,69.4 7.9,73.4 10.6,76.1 10.6,78.2 9.6,79.2 7.57,79.2 JP9.1
  Bottom 0.15: v24.3,11.2 24.3,6.7 v22.7,5.1
N$47  (via drill 0.3)
  Top 0.15: U$21.P$1 25.3,16.6 25.1,16.4 v25.1,10.4 | v23.3,4.4 22.3,4.4 22,4.7 11.7,4.7 9.3,7.1 9.3,11.1 3.8,16.6 3.8,65.9 7.5,69.6 JP9.2
  Bottom 0.15: v25.1,10.4 25.1,6.2 v23.3,4.4
N$48  (via drill 0.3)
  Top 0.15: U$22.P$2 75.2,17.1 76.1,16.2 76.1,10.5 v76.5,10.1 | v78.9,6.7 86.9,6.7 96.8,16.6 96.8,64.2 91.6,69.4 91.6,73.1 89.4,75.3 89.4,78 90.7,79.3 91.47,79.3 JP10.1
  Bottom 0.15: v76.5,10.1 76.5,8.4 78.2,6.7 v78.9,6.7
N$49  (via drill 0.3)
  Top 0.15: U$22.P$1 75,16.6 75.7,15.9 v75.7,9.5 | v78.2,6 86.8,6 97.2,16.4 97.2,64.4 92,69.6 92,76.23 JP10.2
  Bottom 0.15: v75.7,9.5 75.7,8.5 v78.2,6
N$50
  Top 0.15: U$3.GA2(69) 80.8,49.4 81.2,49 83.9,49 84.7,49.8 84.95,49.8 R27.1
N$56
  Top 0.15: U$3.IREF(33,34) 81.8,43.85 R28.2
N$57
  Top 0.15: U$3.GA1(68) 80.65,49.05 81.1,48.6 85.15,48.6 R26.1
N$58
  Top 0.15: U$3.GA0(67) 80.5,48.7 81,48.2 84,48.2 84.7,47.5 85.05,47.5 R25.1
N$59  (via drill 0.3)
  Top 0.15: U$3.RESET1(45) 80.65,45.45 v81,45.1 C11.1 R21.1
  Bottom 0.15: C11.1 v81,45.1
N$60  (via drill 0.3)
  Top 0.15: U$3.RESET2(56) v81,47.2 R22.1 C12.1
  Bottom 0.15: C12.1 R22.1 v81,47.2
N$61  (via drill 0.3)
  Top 0.15: U$3.RESET3(88) 80.35,51.75 80.4,51.7 80.4,51.3 v81,50.7 81.4,50.3 R23.1
  Bottom 0.15: C13.1 81.3,50.4 v81,50.7
N$62  (via drill 0.3)
  Top 0.15: U$3.RESET4(89) 80.75,52.05 v81,51.8 81.65,51.8 R24.1
  Bottom 0.15: C14.1 81.75,51.8 v81,51.8
N$64
  Top 0.15: U$3.VTHR(24,16) 80.8,42.1 81.1,42.4 81.75,42.4 R29.2
N$73
  Top 0.15: R34.1 85.15,27.6 84.6,27.6 83.9,28.3 80.8,28.3 80.4,28.7 U$4.GA0(67)
N$74
  Top 0.15: R35.1 85.05,28.6 81,28.6 80.55,29.05 U$4.GA1(68)
N$75
  Top 0.15: R36.1 84.95,29.8 84.7,29.8 83.8,28.9 81.2,28.9 80.7,29.4 U$4.GA2(69)
N$76  (via drill 0.3)
  Top 0.15: U$4.RESET1(45) 80.65,25.45 v81,25.1 C15.1 R30.1
  Bottom 0.15: C15.1 v81,25.1
N$77  (via drill 0.3)
  Top 0.15: U$4.RESET2(56) v81,27.2 R31.1
  Bottom 0.15: C16.1 R31.1 v81,27.2
N$78  (via drill 0.3)
  Top 0.15: U$4.RESET3(88) 80.35,31.75 80.4,31.7 80.4,31.3 v81,30.7 81.3,30.4 81.85,30.4 R32.1
  Bottom 0.15: C17.1 81.65,30.4 81.3,30.4 v81,30.7
N$79  (via drill 0.3)
  Top 0.15: U$4.RESET4(89) 80.65,32.05 v81,31.7 81.65,31.7 R33.1
  Bottom 0.15: C18.1 81.1,31.6 v81,31.7
N$80
  Top 0.15: U$4.IREF(33,34) 81.7,23.85 R37.2
N$81
  Top 0.15: U$4.VTHR(24,16) 80.8,22.1 81,22.3 81.75,22.3 R38.2
NTC1+
  Top 0.15: J1.2-3 32.33,89.9 37.6,89.9 39,88.5 39,84.4 37.7,83.1 36.9,83.1 35.47,81.67 JP5.1
NTC1-
  Top 0.15: J1.2-6 36.18,87.4 37.8,87.4 38.6,86.6 38.6,84.7 37.5,83.6 35.1,83.6 32.9,81.4 32.9,79.63 JP5.2
NTC2+
  Top 0.15: J1.1-3 18.36,89.9 24,89.9 25.5,88.4 25.5,82.53 JP6.1
NTC2-
  Top 0.15: J1.1-6 22.21,87.4 24.3,87.4 25,86.7 25,85.4 24.4,84.8 23.4,84.8 23,84.4 23,82.57 JP6.2
NTC3+
  Top 0.15: J2.1-3 66.46,90 71.3,90 73.1,88.2 73.1,82.57 JP7.1
NTC3-
  Top 0.15: J2.1-6 70.21,87.4 72,87.4 72.6,86.8 72.6,85.2 72.1,84.7 71,84.7 70.6,84.3 70.6,82.53 JP7.2
NTC4+
  Top 0.15: J2.2-3 80.53,90.1 85.5,90.1 87.3,88.3 87.3,82.57 JP8.1
NTC4-
  Top 0.15: J2.2-6 84.18,87.4 86.1,87.4 86.8,86.7 86.8,85.4 86.2,84.8 85.3,84.8 84.8,84.3 84.8,82.53 JP8.2
VDDA  (via drill 0.3, 0.3 pad 0.7)
  Top 0.3: R21.2 v84,45 85.2,45 85.7,44.5 85.7,43.65 C47.1 87.15,43.55 v89.7,41 | R22.2 v84,47.2 | R30.2 v84.1,25 84.3,25 84.9,24.4 | R31.2 v84.1,27.2 | R4.2 v15.9,53.2 | R3.2 v15.9,55.4 15.85,55.45 C39.1 14.65,55.4 v13.5,55.4 13.5,58.8 17.9,63.2 v19.7,63.2 | R12.2 v15.9,35.4 14.7,36.6 14.7,43.5 v15.4,44.2 | C35.1 U$1.VDDA C36.1 U$2.VDDA 21.85,20.7 C40.1 | 21.85,63.35 v21.8,63.2 | R13.2 v15.9,33.2 | C43.1 U$3.VDDA C44.1 U$4.VDDA v78.15,19.55 v78.1,19.5 C48.1 | 84.9,24.4 88.9,24.4 v91.3,26.8 | v80.4,20.6 81.2,19.8 84.2,19.8 84.9,20.5 84.9,24.4
  Top 0.5: C35.1 21.85,63.2 v21.8,63.2 | C43.1 78.15,62.25
  Top 1: v31,72.3 v30.2,72.3 v29.4,72.3 v28.6,72.3 v27.8,72.3 24.9,69.4 24.9,66.4 21.85,63.35 | 78.15,62.25 74.6,65.8 74.6,69.6 v71.9,72.3 v71.1,72.3 v70.3,72.3 v69.5,72.3 v68.7,72.3 | X1.3 52.1,79 58.8,72.3 v60,72.3 v60.8,72.3 v61.6,72.3 v62.4,72.3 v63.2,72.3
  Bottom 0.3: v84,47.2 v84,45 | v15.9,55.4 v15.9,53.2 | v19.7,63.2 v21.8,63.2 | v13.5,55.4 13.5,49.3 14.4,48.4 14.4,45.2 v15.4,44.2 | v15.9,33.2 v15.9,35.4 | v91.3,26.8 91.3,39.4 v89.7,41 | v84.1,27.2 v84.1,25
  Bottom 0.5: v78.15,19.55 79.35,19.55 v80.4,20.6
  Bottom 1: 48,72.3 v27.8,72.3 | C63.+ 47.9,72.2 48,72.3 | 48,72.3 v63.2,72.3 v68.7,72.3 v71.9,72.3
VDDD  (via drill 0.3 pad 0.7)
  Top 0.15: R23.2 83.15,49.65 82.9,49.4 81.3,49.4 80.9,49.8 79.45,49.8 | R32.2 83.15,29.45 83,29.3 81.3,29.3 80.7,29.9 79.45,29.9 U$4.VDDD | R5.2 16.85,50.95 17.1,51.2 18.6,51.2 19.3,50.5 20.55,50.5 | R14.2 16.85,30.95 17,31.1 18.6,31.1 19.2,30.5 20.55,30.5 20.55,30.2
  Top 0.3: U$3.VDDD 79.45,40.1 80.35,40.1 C46.1 C49.1 79.45,36.8 79.45,29.9 | R23.2 R24.2 85.9,51.6 86.55,50.95 R27.2 R26.2 R25.2 | U$3.VDDD 79.45,49.8 | R32.2 R33.2 86.2,31.5 86.55,31.15 R36.2 R35.2 R34.2 | R54.1 C53.2 78.6,15.7 79.5,16.6 | R72.1 83.1,15.8 82.3,16.6 79.5,16.6 | 20.55,43.5 20.55,50.5 U$1.VDDD 20.55,59.5 19.65,59.5 19.45,59.7 C37.1 | 20.55,43.5 20.55,42.85 | R7.2 R8.2 R9.2 13.4,50.25 13.4,49.2 13.8,48.8 16.75,48.8 R6.2 R5.2 | R50.1 20.05,65.6 20.05,64.85 | R16.2 R17.2 R18.2 13.45,29.25 13.9,28.8 16.75,28.8 R15.2 R14.2 | 21.65,14.9 R52.1 C52.2 23.2,16.4 22.3,17.3 20.5,17.3 | 20.5,17.3 19.5,17.3 18.4,16.2 R70.1 | 78.4,65.55 R56.1 78.7,65.45 78.7,64.9 79.6,64 | 20.5,17.3 20.55,17.35 C42.1 20.55,30.2 U$2.VDDD 20.55,39.55 19.75,39.55 19.5,39.8 19.5,40.45 C41.1 C38.1 19.55,43.5 20.55,43.5 | C51.2 16.8,64.05 R68.1 | C51.2 19.2,64 20.05,64.85 | 16.8,63.95 C51.2 | U$4.VDDD C50.1 79.45,16.65 79.5,16.6 | U$3.VDDD 79.45,57.5 C45.1 80.5,57.5 | 20.05,64.85 20.65,64.25 20.75,64.25 | R74.1 81.75,65.5 C54.2 81.65,64 79.6,64 | 79.6,64 78.95,63.35
  Top 0.5: C37.1 19.45,61.65 20.75,62.95 20.75,64.25 | 80.5,57.5 80.5,61.3
  Top 1: 20.75,64.25 23.5,67 23.5,69.9 27.2,73.6 v28.6,73.6 v29.4,73.6 v30.2,73.6 v31,73.6 v31.8,73.6 | v67.9,73.6 v68.7,73.6 v69.5,73.6 v70.3,73.6 v71.1,73.6 72.5,73.6 75.9,70.2 75.9,66.4 78.95,63.35 80.5,61.8 80.5,61.3
  Bottom 1: v31.8,73.6 56.3,73.6 | 56.3,73.6 C64.+ X1.4 | v67.9,73.6 56.3,73.6

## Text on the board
Top: Hit | OR | C | T | T | C | T1 | T3 | T4 | T2 | V | V | HV | Liverpool University I.T. May 2013 | Quad Pixel Rigid Board V2.0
